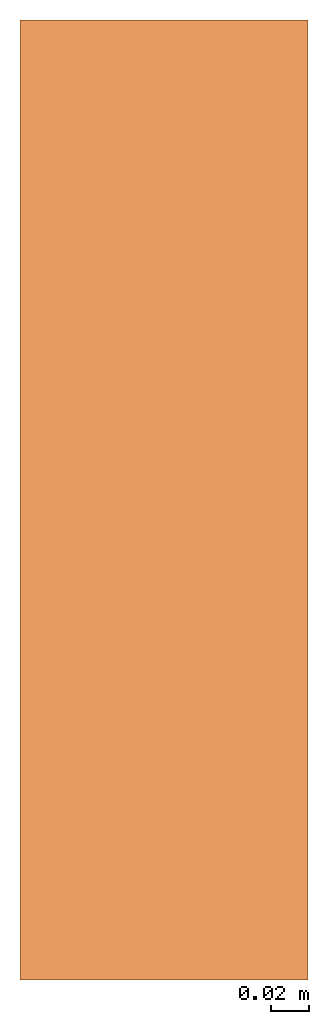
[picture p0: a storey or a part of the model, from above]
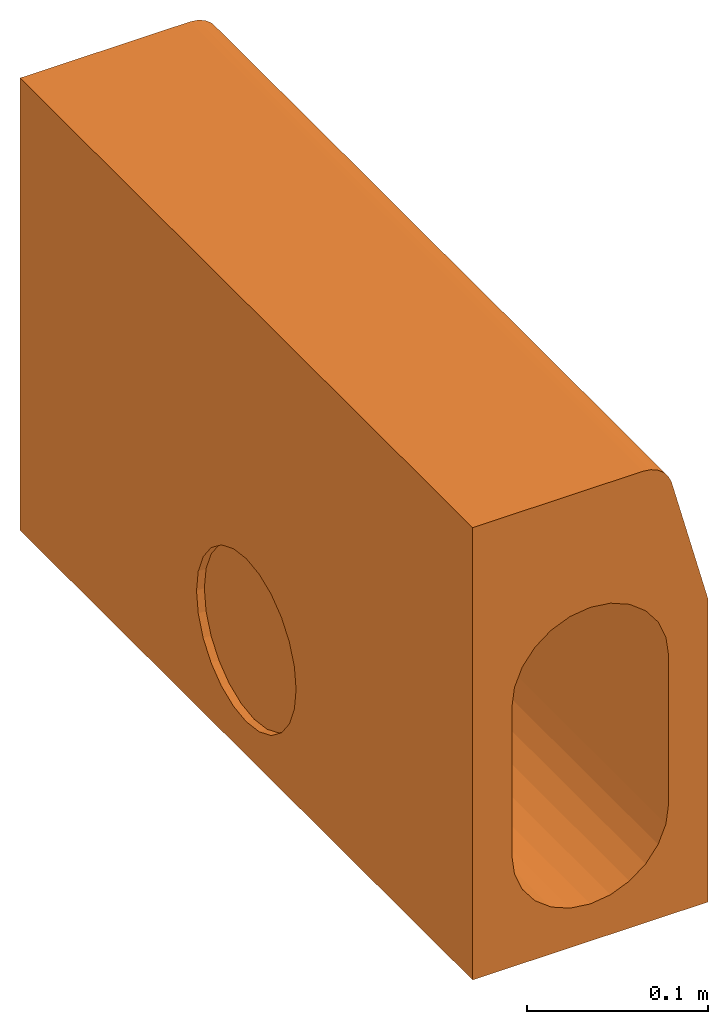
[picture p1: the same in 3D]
Properties of the parts of a building model (IFC2X3)

# File
Description: ViewDefinition [CoordinationView]
File name: 7972 - Blind unit - 500mm LG.ifc
Time: 2013-09-12T12:45:38
Written by: Autodesk Revit 2013
Made in: 20120221_2030(x64)

# IfcProject, Project Number
LongName: Project Name; Phase: Project Status

# IfcSite, Default
RefLatitude: 42, 21, 30, 344238; RefLongitude: -71, -3, -35, -194702; RefElevation: 0 mm

# IfcBuilding
Pset_BuildingCommon - NumberOfStoreys: 2
Other - Project Number: Project Number; Project Status: Project Status; Project Address: Enter address here; Project Name: Project Name; Client Name: Owner; Project Issue Date: Issue Date

# IfcBuildingStorey (2)
Constraints - Elevation Base: 0
Graphics - Symbol at End 2 Default: yes; Color: 0; Symbol at End 1 Default: no; Symbol: M_Level Head - Circle: M_Level Head - Circle; Line Weight: 1; Line Pattern: Center
Identity Data - Structural: no; Building Story: yes
Dimensions - Computation Height: 0 mm
Name | LongName = Name | Elevation (mm) = Constraints, Elevation (mm)
T.O. Fnd. Wall | T.O. Fnd. Wall | -300
Level 1 | Level 1 | 0

# IfcBuildingElementProxy: 7972 - Blind unit - 500mm LG, Civil-Drainage-Channel-ACO-KerbDrain-HB305 - PART 1:7972 - Blind unit - 500mm LG:7972 - Blind unit - 500mm LG:255899
In: T.O. Fnd. Wall
Material: ACO Polymer Concrete.
Materials and Finishes - Channel Material: Vienite® Synthetic Resin Concrete; Connection Pipe Material: N/A; Channel Colour: Grey; Access Cover/Frame Material: N/A; End Cap Material: N/A; Connection Pipe Material Colour: N/A; Access Cover/Frame Finish: N/A; End Cap Colour: N/A; Access Cover/Frame Colour: N/A
Dimensions - I/O Endcap Void depth: 6000 mm; Staright Void Depth: -180 mm; Void_Length: 500 mm; Void_Width: 150 mm; Volume: 13210409 mm3
Constraints - Level: Level: Level 1; Moves With Nearby Elements: no
Phasing - Phase Created: Phase 1
Pset_BuildingElementProxyCommon - Reference: 7972 - Blind unit - 500mm LG
Construction - I/O Pipe: no; KDHB305 - Access Unit: no; KDHB305 - Perforated centre stone: no; KDHB305 - LH Inlet/Outlet end cap: no; KDHB305 - Centre stone: no; KDHB305 - LH drop kerb: no; KDHB305 - RH drop kerb: no; KDHB305 - Channel unit - 250mm: no; KDHB305 - Flush RH dropkerb: no; KDHB305 - Channel unit - 500mm: no; KDHB305 - Blind unit: yes; KDHB305 - Flush LH dropkerb: no; KDHB305 - Drainable centre stone: no; KDHB305 - Closing end cap: no; KDHB305 - Channel unit - 1000mm: no; KDHB305 - RH Inlet/outlet end cap: no
Data - Product Weight: 28.5 Kg; Concrete Surround Volume - Load Class A 15 - D 400 - Concrete Pavement: 0.14m³/m; Channel C.S.A: 0.02m²; Product Dimensions: 500mm x 150mm x 305mm (LxWxH); Connection Pipe O.D: N/A; Concrete Surround Volume - Load Class A 15 - D 400 - Grass or Asphalt Pavement: 0.13m³/m; ACO Hydraulic Design Software: http://www.acodesign.co.uk; Load Class: A 15 - D 400; Hydraulic Performance: http://www.aco.co.uk/download.php?id=120; Invert Depth: 280mm; Installation - Concrete Grade: Refer to brochure; Product Standard: BS EN 1433:2002, CE marked, Kitemarked; Drainage Slot Intake area: N/A; Drainage Slot Width: N/A
Other - CreatedBy: www.aco.co.uk; Revision: 1
Identity Data - Assembly Code: D2040; Manufacturer: ACO Technologies plc - ACO Water Management Division; Product Code: 7972; Fax: +44 (0)1462 815895; Address: ACO Business Park, Hitchin Road, Shefford, Bedfordshire, United Kingdom SG17 5TE; URL: www.aco.co.uk; Telephone: +44 (0)1462 816666; Type Comments: ACO KerbDrain HB305 half battered blind kerb unit 500mm long; OmniClass Number: 23.70.50.24; Assembly Description: Rain Water Drainage; Installation guidelines: http://www.aco.co.uk/download.php?id=120; Cost: 0; Maintenance guidelines: http://www.aco.co.uk/download.php?id=120; OmniClass Title: Rainwater Removal; Model Description: Combined kerb and drainage system; Product brochure: http://www.aco.co.uk/download.php?id=120; Model: ACO KerbDrain HB305; Price: POA - contact ACO; E-mail Technical: technical@aco.co.uk; Product Page URL: http://www.aco.co.uk/product_detail.php?id=3; E-mail Sales: customersupport@aco.co.uk
General - TagNumber: 0.000000; SerialNumber: 0.000000
Green Building Properties - End Cap Recycled Material Content: N/A; Access Cover/Frame Recyclable: N/A; End Cap Recyclable: N/A; Access Cover/Frame Recycled Material Content: N/A; Channel Recycled Material Content: 20% minimum; Channel Recyclable: Fully recyclable

# IfcOpeningElement: Recess (2)
In: Level 1
Dimensions - Area: 53016081 mm2; Volume: 21192932206 mm3; Perimeter: 29157.2 mm; Thickness: 400 mm
Constraints - Height Offset From Level: 0 mm; Room Bounding: yes; Related to Mass: no; Level: Level: Level 1
Structural - Enable Analytical Model: no; Structural: no
Phasing - Phase Created: Phase 1
Graphics - Coarse Scale Fill Color: 0
Analytical Properties - Roughness: 1; Absorptance: 0.1
Construction - Default Thickness: 400 mm; Function: 0

# IfcSlab: Floor:Generic Floor - 400mm, Floor:Generic Floor - 400mm:184025
In: Level 1
PredefinedType: FLOOR; Material: Default Floor 400 mm
Dimensions - Area: 53016081 mm2; Volume: 21192932206 mm3; Perimeter: 29157.2 mm; Thickness: 400 mm
Constraints - Height Offset From Level: 0 mm; Room Bounding: yes; Related to Mass: no; Level: Level: Level 1
Structural - Enable Analytical Model: no; Structural: no
Phasing - Phase Created: Phase 1
Pset_SlabCommon - Reference: Generic Floor - 400mm; IsExternal: no; LoadBearing: yes
Graphics - Coarse Scale Fill Color: 0
Analytical Properties - Roughness: 1; Absorptance: 0.1
Construction - Default Thickness: 400 mm; Function: 0
